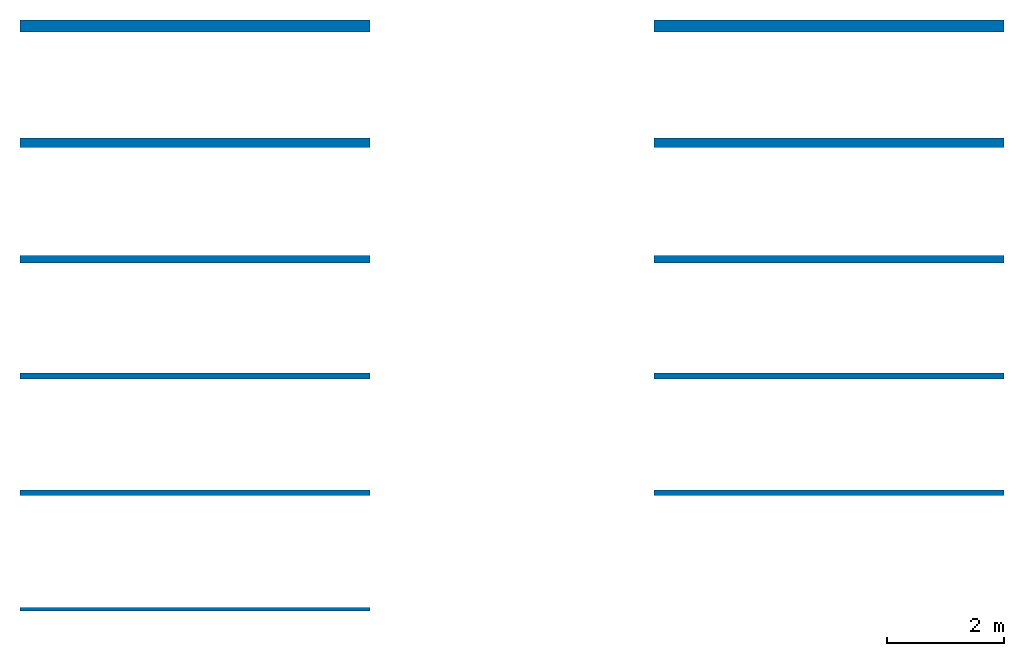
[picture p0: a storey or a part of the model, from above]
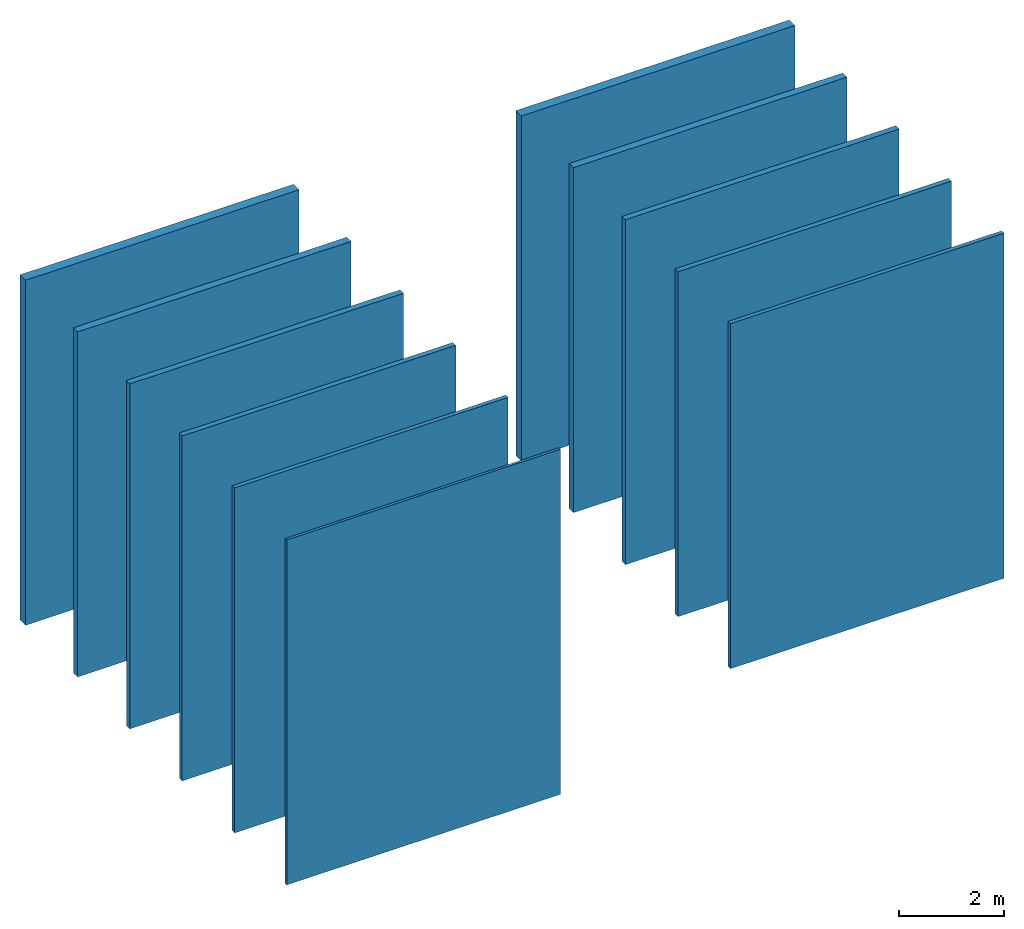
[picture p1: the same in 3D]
Properties of the parts of a building model (IFC2X3)

# File
Description: ViewDefinition [CoordinationView]
File name: Numero
Time: 2019-05-03T09:54:18
Written by: The EXPRESS Data Manager Version 5.02.0100.07 : 28 Aug 2013
Made in: 20150220_1215(x64) - Exporter 16.0.428.0 - Default UI
Comment: STEP Physical File produced by: The EXPRESS Data Manager Version 5.02.0100.07 : 28 Aug 2013 * Module: EDMstepFileFactory/EDMstandAlone * Creation date: Fri May 03 09:54:18 2019 * Host: HP-RS * Database: C:\Users\EKORU_~1\AppData\Local\Temp\{C8AE7AAE-09B5-4A10-BCEE-8D542912D24F}\ifc * Database version: 5507 * Database creation date: Fri May 03 09:54:18 2019 * Schema: IFC2X3 * Model: DataRepository.ifc * Model creation date: Fri May 03 09:54:18 2019 * Header model: DataRepository.ifc_HeaderModel * Header model creation date: Fri May 03 09:54:18 2019 * EDMuser: sdai-user * EDMgroup: sdai-group * License ID and type: 5605 : Permanent license. Expiry date: * EDMstepFileFactory options: 020000

# IfcProject, Numero
LongName: Nome; Phase: Stato

# IfcSite, Default
RefLatitude: 41, 47, 59, 999999; RefLongitude: 12, 35, 59, 999999; RefElevation: 0 mm
Altro - Categoria: Informazioni sul progetto; Data di consegna del progetto: Data; Indirizzo del progetto: Immettere l'indirizzo; Nome del cliente: Proprietario; Nome del progetto: Nome; Numero del progetto: Numero; Stato del progetto: Stato

# IfcBuilding
Pset_BuildingCommon - NumberOfStoreys: 1
Altro - Categoria: Informazioni sul progetto; Data di consegna del progetto: Data; Indirizzo del progetto: Immettere l'indirizzo; Nome del cliente: Proprietario; Nome del progetto: Nome; Numero del progetto: Numero; Stato del progetto: Stato

# IfcBuildingStorey, Livello 1
LongName: Livello 1; Elevation: 0 mm
Vincoli - Base quota altimetrica: Punto base progetto; Quota altimetrica: 0 mm
Altro - Categoria: Livelli; Famiglia: Livello: Estremità 8 mm; Famiglia e tipo: Livello: Estremità 8 mm; ID tipo: Livello: Estremità 8 mm; Tipo: Livello: Estremità 8 mm; Nome famiglia: Livello
Dati identità - Strutturale: no; Nome: Livello 1; Piano edificio: yes; Nome del tipo: Estremità 8 mm
Dimensioni - Altezza di calcolo: 0 mm
Grafica - Colore: 0; Modello di linea: Centro; Simbolo: Estremità del livello - Cerchio: Estremità del livello - Cerchio; Simbolo a estremità 1 per default: no; Simbolo a estremità 2 per default: yes; Spessore di linea: 1

# IfcWallStandardCase: Muro di base:Sistema GASBETON Evolution sp. 110 mm per tramezzatura, Muro di base:Sistema GASBETON Evolution sp. 110 mm per tramezzatura:162390
In: Livello 1
Type - PredefinedType: STANDARD; Material: GASBETON Incollarasa 5 mm, GASBETON Evolution 100 mm, GASBETON Incollarasa 5 mm
Type - Altro - Categoria: Muri; Nome famiglia: Muro di base
Type - Costruzione - Funzione: Esterno; Ripiegatura agli inserti: Non ripiegare; Ripiegatura alle estremità: Nessuno; Larghezza: 110 mm
Type - Dati identità - Descrizione: Parete rifinita formata dalla seguente stratigrafia (dall'esterno verso l'interno): rasatura armata con Incollarasa e rete da intonaco GASBETON, blocchi GASBETON Evolution, rasatura armata con Incollarasa e rete da intonaco GASBETON; Installation Guide: http://www.gasbeton.it/wp-content/uploads/2017/11/GASBETON-Guida-alla-progettazione.pdf; Modello: Soluzione tramezzatura Gasbeton Evolution; Nome del tipo: Sistema GASBETON Evolution sp. 110 mm per tramezzatura; Product data url: www.gasbeton.it; Produttore: EKORU s.r.l.; Resistenza al fuoco: EI 180; Euroclasse A1; Techinical data sheet: http://www.gasbeton.it/download/; URL: http://www.ekoru.it/; Youtube channel: https://www.youtube.com/user/bacchispa
Type - Generale - Edition number: 1; Manufacturer country: Italy; Manufacturer name: EKORU s.r.l.; Product family: walls
Type - Grafica - Colore del retino a dettaglio basso: 0
Type - Materiali e finiture - Materiale strutturale: GASBETON Evolution; Material main: Autoclaved Aerated Concrete (AAC)
Type - Proprietà analitiche - Ruvidità: 2; Assorbimento: 0.7; Coefficiente di scambio termico (U): 0.24971; Massa termica: 209837; Resistenza termica (R): 4.00464
Altro - Famiglia: Muro di base: Sistema GASBETON Evolution sp. 110 mm per tramezzatura; Famiglia e tipo: Muro di base: Sistema GASBETON Evolution sp. 110 mm per tramezzatura; ID tipo: Muro di base: Sistema GASBETON Evolution sp. 110 mm per tramezzatura; Tipo: Muro di base: Sistema GASBETON Evolution sp. 110 mm per tramezzatura
Dimensioni - Area: 48 m2; Lunghezza: 6000 mm; Volume: 5.28 m3
Fasi - Fase di creazione: Fase 1
Strutturale - Attiva modello analitico: no; Strutturale: no; Utilizzo strutturale: Non portante
Vincoli - Delimita il locale: yes; Distanza estensione base: 0 mm; Distanza estensione superiore: 0 mm; La base è associata: no; La parte superiore è associata: no; Linea di ubicazione: Linea d'asse del muro; Offset base: 0 mm; Offset superiore: 0 mm; Relativo a massa: no; Vincolo di base: Livello: Livello 1; Altezza non collegata: 8000 mm
Pset_WallCommon - LoadBearing: no; ExtendToStructure: no; IsExternal: yes; Reference: Sistema GASBETON Evolution sp. 110 mm per tramezzatura; FireRating: EI 180; Euroclasse A1; ThermalTransmittance: 0.24971 kg/K/s3
Pset_ManufacturerTypeInformation - Manufacturer: EKORU s.r.l.

# IfcWallStandardCase: Muro di base:Sistema GASBETON Evolution sp. 130 mm per tramezzatura, Muro di base:Sistema GASBETON Evolution sp. 130 mm per tramezzatura:162386
In: Livello 1
Type - PredefinedType: STANDARD; Material: GASBETON Incollarasa 5 mm, GASBETON Evolution 120 mm, GASBETON Incollarasa 5 mm
Type - Altro - Categoria: Muri; Nome famiglia: Muro di base
Type - Costruzione - Funzione: Esterno; Ripiegatura agli inserti: Non ripiegare; Ripiegatura alle estremità: Nessuno; Larghezza: 130 mm
Type - Dati identità - Descrizione: Parete rifinita formata dalla seguente stratigrafia (dall'esterno verso l'interno): rasatura armata con Incollarasa e rete da intonaco GASBETON, blocchi GASBETON Evolution, rasatura armata con Incollarasa e rete da intonaco GASBETON; Installation Guide: http://www.gasbeton.it/wp-content/uploads/2017/11/GASBETON-Guida-alla-progettazione.pdf; Modello: Soluzione tramezzatura Gasbeton Evolution; Nome del tipo: Sistema GASBETON Evolution sp. 130 mm per tramezzatura; Product data url: www.gasbeton.it; Produttore: EKORU s.r.l.; Resistenza al fuoco: EI 180; Euroclasse A1; Techinical data sheet: http://www.gasbeton.it/download/; URL: http://www.ekoru.it/; Youtube channel: https://www.youtube.com/user/bacchispa
Type - Generale - Edition number: 1; Manufacturer country: Italy; Manufacturer name: EKORU s.r.l.; Product family: walls
Type - Grafica - Colore del retino a dettaglio basso: 0
Type - Materiali e finiture - Materiale strutturale: GASBETON Evolution; Material main: Autoclaved Aerated Concrete (AAC)
Type - Proprietà analitiche - Ruvidità: 2; Assorbimento: 0.7; Coefficiente di scambio termico (U): 0.208314; Massa termica: 249308; Resistenza termica (R): 4.80044
Altro - Famiglia: Muro di base: Sistema GASBETON Evolution sp. 130 mm per tramezzatura; Famiglia e tipo: Muro di base: Sistema GASBETON Evolution sp. 130 mm per tramezzatura; ID tipo: Muro di base: Sistema GASBETON Evolution sp. 130 mm per tramezzatura; Tipo: Muro di base: Sistema GASBETON Evolution sp. 130 mm per tramezzatura
Dimensioni - Area: 48 m2; Lunghezza: 6000 mm; Volume: 6.24 m3
Fasi - Fase di creazione: Fase 1
Strutturale - Attiva modello analitico: no; Strutturale: no; Utilizzo strutturale: Non portante
Vincoli - Delimita il locale: yes; Distanza estensione base: 0 mm; Distanza estensione superiore: 0 mm; La base è associata: no; La parte superiore è associata: no; Linea di ubicazione: Linea d'asse del muro; Offset base: 0 mm; Offset superiore: 0 mm; Relativo a massa: no; Vincolo di base: Livello: Livello 1; Altezza non collegata: 8000 mm
Pset_WallCommon - LoadBearing: no; ExtendToStructure: no; IsExternal: yes; Reference: Sistema GASBETON Evolution sp. 130 mm per tramezzatura; FireRating: EI 180; Euroclasse A1; ThermalTransmittance: 0.208314 kg/K/s3
Pset_ManufacturerTypeInformation - Manufacturer: EKORU s.r.l.

# IfcWallStandardCase: Muro di base:Sistema GASBETON Evolution sp. 160 mm per tramezzatura, Muro di base:Sistema GASBETON Evolution sp. 160 mm per tramezzatura:162382
In: Livello 1
Type - PredefinedType: STANDARD; Material: GASBETON Incollarasa 5 mm, GASBETON Evolution 150 mm, GASBETON Incollarasa 5 mm
Type - Altro - Categoria: Muri; Nome famiglia: Muro di base
Type - Costruzione - Funzione: Esterno; Ripiegatura agli inserti: Non ripiegare; Ripiegatura alle estremità: Nessuno; Larghezza: 160 mm
Type - Dati identità - Descrizione: Parete rifinita formata dalla seguente stratigrafia (dall'esterno verso l'interno): rasatura armata con Incollarasa e rete da intonaco GASBETON, blocchi GASBETON Evolution, rasatura armata con Incollarasa e rete da intonaco GASBETON; Installation Guide: http://www.gasbeton.it/wp-content/uploads/2017/11/GASBETON-Guida-alla-progettazione.pdf; Modello: Soluzione tramezzatura Gasbeton Evolution; Nome del tipo: Sistema GASBETON Evolution sp. 160 mm per tramezzatura; Product data url: www.gasbeton.it; Produttore: EKORU s.r.l.; Resistenza al fuoco: EI 180; Euroclasse A1; Techinical data sheet: http://www.gasbeton.it/download/; URL: http://www.ekoru.it/; Youtube channel: https://www.youtube.com/user/bacchispa
Type - Generale - Edition number: 1; Manufacturer country: Italy; Manufacturer name: EKORU s.r.l.; Product family: walls
Type - Grafica - Colore del retino a dettaglio basso: 0
Type - Materiali e finiture - Materiale strutturale: GASBETON Evolution; Material main: Autoclaved Aerated Concrete (AAC)
Type - Proprietà analitiche - Ruvidità: 2; Assorbimento: 0.7; Coefficiente di scambio termico (U): 0.16683; Massa termica: 308515; Resistenza termica (R): 5.99414
Altro - Famiglia: Muro di base: Sistema GASBETON Evolution sp. 160 mm per tramezzatura; Famiglia e tipo: Muro di base: Sistema GASBETON Evolution sp. 160 mm per tramezzatura; ID tipo: Muro di base: Sistema GASBETON Evolution sp. 160 mm per tramezzatura; Tipo: Muro di base: Sistema GASBETON Evolution sp. 160 mm per tramezzatura
Dimensioni - Area: 48 m2; Lunghezza: 6000 mm; Volume: 7.68 m3
Fasi - Fase di creazione: Fase 1
Strutturale - Attiva modello analitico: no; Strutturale: no; Utilizzo strutturale: Non portante
Vincoli - Delimita il locale: yes; Distanza estensione base: 0 mm; Distanza estensione superiore: 0 mm; La base è associata: no; La parte superiore è associata: no; Linea di ubicazione: Linea d'asse del muro; Offset base: 0 mm; Offset superiore: 0 mm; Relativo a massa: no; Vincolo di base: Livello: Livello 1; Altezza non collegata: 8000 mm
Pset_WallCommon - LoadBearing: no; ExtendToStructure: no; IsExternal: yes; Reference: Sistema GASBETON Evolution sp. 160 mm per tramezzatura; FireRating: EI 180; Euroclasse A1; ThermalTransmittance: 0.16683 kg/K/s3
Pset_ManufacturerTypeInformation - Manufacturer: EKORU s.r.l.

# IfcWallStandardCase: Muro di base:Sistema GASBETON Evolution sp. 210 mm per tramezzatura, Muro di base:Sistema GASBETON Evolution sp. 210 mm per tramezzatura:139188
In: Livello 1
Type - PredefinedType: STANDARD; Material: GASBETON Incollarasa 5 mm, GASBETON Evolution 200 mm, GASBETON Incollarasa 5 mm
Type - Altro - Categoria: Muri; Nome famiglia: Muro di base
Type - Costruzione - Funzione: Esterno; Larghezza: 210 mm; Ripiegatura agli inserti: Non ripiegare; Ripiegatura alle estremità: Nessuno
Type - Dati identità - Descrizione: Parete rifinita formata dalla seguente stratigrafia (dall'esterno verso l'interno): rasatura armata con Incollarasa e rete da intonaco GASBETON, blocchi GASBETON Evolution, rasatura armata con Incollarasa e rete da intonaco GASBETON; Installation Guide: http://www.gasbeton.it/wp-content/uploads/2017/11/GASBETON-Guida-alla-progettazione.pdf; Modello: Soluzione tramezzatura Gasbeton Evolution; Nome del tipo: Sistema GASBETON Evolution sp. 210 mm per tramezzatura; Product data url: www.gasbeton.it; Produttore: EKORU s.r.l.; Resistenza al fuoco: EI 180; Euroclasse A1; Techinical data sheet: http://www.gasbeton.it/download/; URL: http://www.ekoru.it/; Youtube channel: https://www.youtube.com/user/bacchispa
Type - Generale - Edition number: 1; Manufacturer country: Italy; Manufacturer name: EKORU s.r.l.; Product family: walls
Type - Grafica - Colore del retino a dettaglio basso: 0
Type - Materiali e finiture - Materiale strutturale: GASBETON Evolution; Material main: Autoclaved Aerated Concrete (AAC)
Type - Proprietà analitiche - Assorbimento: 0.7; Coefficiente di scambio termico (U): 0.125256; Massa termica: 407194; Resistenza termica (R): 7.98364; Ruvidità: 2
Altro - Famiglia: Muro di base: Sistema GASBETON Evolution sp. 210 mm per tramezzatura; Famiglia e tipo: Muro di base: Sistema GASBETON Evolution sp. 210 mm per tramezzatura; ID tipo: Muro di base: Sistema GASBETON Evolution sp. 210 mm per tramezzatura; Tipo: Muro di base: Sistema GASBETON Evolution sp. 210 mm per tramezzatura
Dimensioni - Area: 48 m2; Lunghezza: 6000 mm; Volume: 10.08 m3
Fasi - Fase di creazione: Fase 1
Strutturale - Attiva modello analitico: no; Strutturale: no; Utilizzo strutturale: Non portante
Vincoli - Altezza non collegata: 8000 mm; Delimita il locale: yes; Distanza estensione base: 0 mm; Distanza estensione superiore: 0 mm; La base è associata: no; La parte superiore è associata: no; Linea di ubicazione: Linea d'asse del muro; Offset base: 0 mm; Offset superiore: 0 mm; Relativo a massa: no; Vincolo di base: Livello: Livello 1
Pset_WallCommon - Reference: Sistema GASBETON Evolution sp. 210 mm per tramezzatura; LoadBearing: no; ExtendToStructure: no; IsExternal: yes; FireRating: EI 180; Euroclasse A1; ThermalTransmittance: 0.125256 kg/K/s3
Pset_ManufacturerTypeInformation - Manufacturer: EKORU s.r.l.

# IfcWallStandardCase: Muro di base:Sistema GASBETON Evolution sp. 60 mm per tramezzatura, Muro di base:Sistema GASBETON Evolution sp. 60 mm per tramezzatura:162398
In: Livello 1
Type - PredefinedType: STANDARD; Material: GASBETON Incollarasa 5 mm, GASBETON Evolution 50 mm, GASBETON Incollarasa 5 mm
Type - Altro - Categoria: Muri; Nome famiglia: Muro di base
Type - Costruzione - Funzione: Esterno; Ripiegatura agli inserti: Non ripiegare; Ripiegatura alle estremità: Nessuno; Larghezza: 60 mm
Type - Dati identità - Descrizione: Parete rifinita formata dalla seguente stratigrafia (dall'esterno verso l'interno): rasatura armata con Incollarasa e rete da intonaco GASBETON, blocchi GASBETON Evolution, rasatura armata con Incollarasa e rete da intonaco GASBETON; Installation Guide: http://www.gasbeton.it/wp-content/uploads/2017/11/GASBETON-Guida-alla-progettazione.pdf; Modello: Soluzione tramezzatura Gasbeton Evolution; Nome del tipo: Sistema GASBETON Evolution sp. 60 mm per tramezzatura; Product data url: www.gasbeton.it; Produttore: EKORU s.r.l.; Resistenza al fuoco: Euroclasse A1; Techinical data sheet: http://www.gasbeton.it/download/; URL: http://www.ekoru.it/; Youtube channel: https://www.youtube.com/user/bacchispa
Type - Generale - Edition number: 1; Manufacturer country: Italy; Manufacturer name: EKORU s.r.l.; Product family: walls
Type - Grafica - Colore del retino a dettaglio basso: 0
Type - Materiali e finiture - Materiale strutturale: GASBETON Evolution; Material main: Autoclaved Aerated Concrete (AAC)
Type - Proprietà analitiche - Ruvidità: 2; Assorbimento: 0.7; Coefficiente di scambio termico (U): 0.496243; Massa termica: 111158; Resistenza termica (R): 2.01514
Altro - Famiglia: Muro di base: Sistema GASBETON Evolution sp. 60 mm per tramezzatura; Famiglia e tipo: Muro di base: Sistema GASBETON Evolution sp. 60 mm per tramezzatura; ID tipo: Muro di base: Sistema GASBETON Evolution sp. 60 mm per tramezzatura; Tipo: Muro di base: Sistema GASBETON Evolution sp. 60 mm per tramezzatura
Dimensioni - Area: 48 m2; Lunghezza: 6000 mm; Volume: 2.88 m3
Fasi - Fase di creazione: Fase 1
Strutturale - Attiva modello analitico: no; Strutturale: no; Utilizzo strutturale: Non portante
Vincoli - Delimita il locale: yes; Distanza estensione base: 0 mm; Distanza estensione superiore: 0 mm; La base è associata: no; La parte superiore è associata: no; Linea di ubicazione: Linea d'asse del muro; Offset base: 0 mm; Offset superiore: 0 mm; Relativo a massa: no; Vincolo di base: Livello: Livello 1; Altezza non collegata: 8000 mm
Pset_WallCommon - LoadBearing: no; ExtendToStructure: no; IsExternal: yes; Reference: Sistema GASBETON Evolution sp. 60 mm per tramezzatura; FireRating: Euroclasse A1; ThermalTransmittance: 0.496243 kg/K/s3
Pset_ManufacturerTypeInformation - Manufacturer: EKORU s.r.l.

# IfcWallStandardCase: Muro di base:Sistema GASBETON Evolution sp. 90 mm per tramezzatura, Muro di base:Sistema GASBETON Evolution sp. 90 mm per tramezzatura:162394
In: Livello 1
Type - PredefinedType: STANDARD; Material: GASBETON Incollarasa 5 mm, GASBETON Evolution 80 mm, GASBETON Incollarasa 5 mm
Type - Altro - Categoria: Muri; Nome famiglia: Muro di base
Type - Costruzione - Funzione: Esterno; Ripiegatura agli inserti: Non ripiegare; Ripiegatura alle estremità: Nessuno; Larghezza: 90 mm
Type - Dati identità - Descrizione: Parete rifinita formata dalla seguente stratigrafia (dall'esterno verso l'interno): rasatura armata con Incollarasa e rete da intonaco GASBETON, blocchi GASBETON Evolution, rasatura armata con Incollarasa e rete da intonaco GASBETON; Installation Guide: http://www.gasbeton.it/wp-content/uploads/2017/11/GASBETON-Guida-alla-progettazione.pdf; Modello: Soluzione tramezzatura Gasbeton Evolution; Nome del tipo: Sistema GASBETON Evolution sp. 90 mm per tramezzatura; Product data url: www.gasbeton.it; Produttore: EKORU s.r.l.; Resistenza al fuoco: EI 120; Euroclasse A1; Techinical data sheet: http://www.gasbeton.it/download/; URL: http://www.ekoru.it/; Youtube channel: https://www.youtube.com/user/bacchispa
Type - Generale - Edition number: 1; Manufacturer country: Italy; Manufacturer name: EKORU s.r.l.; Product family: walls
Type - Grafica - Colore del retino a dettaglio basso: 0
Type - Materiali e finiture - Materiale strutturale: GASBETON Evolution; Material main: Autoclaved Aerated Concrete (AAC)
Type - Proprietà analitiche - Ruvidità: 2; Assorbimento: 0.7; Coefficiente di scambio termico (U): 0.311639; Massa termica: 170365; Resistenza termica (R): 3.20884
Altro - Famiglia: Muro di base: Sistema GASBETON Evolution sp. 90 mm per tramezzatura; Famiglia e tipo: Muro di base: Sistema GASBETON Evolution sp. 90 mm per tramezzatura; ID tipo: Muro di base: Sistema GASBETON Evolution sp. 90 mm per tramezzatura; Tipo: Muro di base: Sistema GASBETON Evolution sp. 90 mm per tramezzatura
Dimensioni - Area: 48 m2; Lunghezza: 6000 mm; Volume: 4.32 m3
Fasi - Fase di creazione: Fase 1
Strutturale - Attiva modello analitico: no; Strutturale: no; Utilizzo strutturale: Non portante
Vincoli - Delimita il locale: yes; Distanza estensione base: 0 mm; Distanza estensione superiore: 0 mm; La base è associata: no; La parte superiore è associata: no; Linea di ubicazione: Linea d'asse del muro; Offset base: 0 mm; Offset superiore: 0 mm; Relativo a massa: no; Vincolo di base: Livello: Livello 1; Altezza non collegata: 8000 mm
Pset_WallCommon - LoadBearing: no; ExtendToStructure: no; IsExternal: yes; Reference: Sistema GASBETON Evolution sp. 90 mm per tramezzatura; FireRating: EI 120; Euroclasse A1; ThermalTransmittance: 0.311639 kg/K/s3
Pset_ManufacturerTypeInformation - Manufacturer: EKORU s.r.l.

# IfcWallStandardCase: Muro di base:Sistema GASBETON Evolution+IDRO sp. 110 mm per tramezzatura, Muro di base:Sistema GASBETON Evolution+IDRO sp. 110 mm per tramezzatura:166541
In: Livello 1
Type - PredefinedType: STANDARD; Material: GASBETON Incollarasa 5 mm, GASBETON Evolution 100 mm, GASBETON Incollarasa 5 mm
Type - Altro - Categoria: Muri; Nome famiglia: Muro di base
Type - Costruzione - Funzione: Esterno; Ripiegatura agli inserti: Non ripiegare; Ripiegatura alle estremità: Nessuno; Larghezza: 110 mm
Type - Dati identità - Descrizione: Parete rifinita formata dalla seguente stratigrafia (dall'esterno verso l'interno): rasatura armata con Incollarasa e rete da intonaco GASBETON, blocchi GASBETON Evolution, rasatura armata con Incollarasa e rete da intonaco GASBETON; Installation Guide: http://www.gasbeton.it/wp-content/uploads/2017/11/GASBETON-Guida-alla-progettazione.pdf; Modello: Soluzione tramezzatura Gasbeton Evolution con primo corso idrofobizzato; Nome del tipo: Sistema GASBETON Evolution+IDRO sp. 110 mm per tramezzatura; Product data url: www.gasbeton.it; Produttore: EKORU s.r.l.; Resistenza al fuoco: EI 180; Euroclasse A1; Techinical data sheet: http://www.gasbeton.it/download/; URL: http://www.ekoru.it/; Youtube channel: https://www.youtube.com/user/bacchispa
Type - Generale - Edition number: 1; Manufacturer country: Italy; Manufacturer name: EKORU s.r.l.; Product family: walls
Type - Grafica - Colore del retino a dettaglio basso: 0
Type - Materiali e finiture - Materiale strutturale: GASBETON Evolution; Material main: Autoclaved Aerated Concrete (AAC)
Type - Proprietà analitiche - Ruvidità: 2; Assorbimento: 0.7; Coefficiente di scambio termico (U): 0.207407; Massa termica: 291437; Resistenza termica (R): 4.82145
Altro - Famiglia: Muro di base: Sistema GASBETON Evolution+IDRO sp. 110 mm per tramezzatura; Famiglia e tipo: Muro di base: Sistema GASBETON Evolution+IDRO sp. 110 mm per tramezzatura; ID tipo: Muro di base: Sistema GASBETON Evolution+IDRO sp. 110 mm per tramezzatura; Tipo: Muro di base: Sistema GASBETON Evolution+IDRO sp. 110 mm per tramezzatura
Dimensioni - Area: 48 m2; Lunghezza: 6000 mm; Volume: 5.28 m3
Fasi - Fase di creazione: Fase 1
Strutturale - Attiva modello analitico: no; Strutturale: no; Utilizzo strutturale: Non portante
Vincoli - Delimita il locale: yes; Distanza estensione base: 0 mm; Distanza estensione superiore: 0 mm; La base è associata: no; La parte superiore è associata: no; Linea di ubicazione: Linea d'asse del muro; Offset base: 0 mm; Offset superiore: 0 mm; Relativo a massa: no; Vincolo di base: Livello: Livello 1; Altezza non collegata: 8000 mm
Pset_WallCommon - LoadBearing: no; ExtendToStructure: no; IsExternal: yes; Reference: Sistema GASBETON Evolution+IDRO sp. 110 mm per tramezzatura; FireRating: EI 180; Euroclasse A1; ThermalTransmittance: 0.207407 kg/K/s3
Pset_ManufacturerTypeInformation - Manufacturer: EKORU s.r.l.

# IfcWallStandardCase: Muro di base:Sistema GASBETON Evolution+IDRO sp. 130 mm per tramezzatura, Muro di base:Sistema GASBETON Evolution+IDRO sp. 130 mm per tramezzatura:166540
In: Livello 1
Type - PredefinedType: STANDARD; Material: GASBETON Incollarasa 5 mm, GASBETON Evolution 120 mm, GASBETON Incollarasa 5 mm
Type - Altro - Categoria: Muri; Nome famiglia: Muro di base
Type - Costruzione - Funzione: Esterno; Ripiegatura agli inserti: Non ripiegare; Ripiegatura alle estremità: Nessuno; Larghezza: 130 mm
Type - Dati identità - Descrizione: Parete rifinita formata dalla seguente stratigrafia (dall'esterno verso l'interno): rasatura armata con Incollarasa e rete da intonaco GASBETON, blocchi GASBETON Evolution, rasatura armata con Incollarasa e rete da intonaco GASBETON; Installation Guide: http://www.gasbeton.it/wp-content/uploads/2017/11/GASBETON-Guida-alla-progettazione.pdf; Modello: Soluzione tramezzatura Gasbeton Evolution con primo corso idrofobizzato; Nome del tipo: Sistema GASBETON Evolution+IDRO sp. 130 mm per tramezzatura; Product data url: www.gasbeton.it; Produttore: EKORU s.r.l.; Resistenza al fuoco: EI 180; Euroclasse A1; Techinical data sheet: http://www.gasbeton.it/download/; URL: http://www.ekoru.it/; Youtube channel: https://www.youtube.com/user/bacchispa
Type - Generale - Edition number: 1; Manufacturer country: Italy; Manufacturer name: EKORU s.r.l.; Product family: walls
Type - Grafica - Colore del retino a dettaglio basso: 0
Type - Materiali e finiture - Materiale strutturale: GASBETON Evolution; Material main: Autoclaved Aerated Concrete (AAC)
Type - Proprietà analitiche - Ruvidità: 2; Assorbimento: 0.7; Coefficiente di scambio termico (U): 0.172992; Massa termica: 347228; Resistenza termica (R): 5.78061
Altro - Famiglia: Muro di base: Sistema GASBETON Evolution+IDRO sp. 130 mm per tramezzatura; Famiglia e tipo: Muro di base: Sistema GASBETON Evolution+IDRO sp. 130 mm per tramezzatura; ID tipo: Muro di base: Sistema GASBETON Evolution+IDRO sp. 130 mm per tramezzatura; Tipo: Muro di base: Sistema GASBETON Evolution+IDRO sp. 130 mm per tramezzatura
Dimensioni - Area: 48 m2; Lunghezza: 6000 mm; Volume: 6.24 m3
Fasi - Fase di creazione: Fase 1
Strutturale - Attiva modello analitico: no; Strutturale: no; Utilizzo strutturale: Non portante
Vincoli - Delimita il locale: yes; Distanza estensione base: 0 mm; Distanza estensione superiore: 0 mm; La base è associata: no; La parte superiore è associata: no; Linea di ubicazione: Linea d'asse del muro; Offset base: 0 mm; Offset superiore: 0 mm; Relativo a massa: no; Vincolo di base: Livello: Livello 1; Altezza non collegata: 8000 mm
Pset_WallCommon - LoadBearing: no; ExtendToStructure: no; IsExternal: yes; Reference: Sistema GASBETON Evolution+IDRO sp. 130 mm per tramezzatura; FireRating: EI 180; Euroclasse A1; ThermalTransmittance: 0.172992 kg/K/s3
Pset_ManufacturerTypeInformation - Manufacturer: EKORU s.r.l.

# IfcWallStandardCase: Muro di base:Sistema GASBETON Evolution+IDRO sp. 160 mm per tramezzatura, Muro di base:Sistema GASBETON Evolution+IDRO sp. 160 mm per tramezzatura:166539
In: Livello 1
Type - PredefinedType: STANDARD; Material: GASBETON Incollarasa 5 mm, GASBETON Evolution 150 mm, GASBETON Incollarasa 5 mm
Type - Altro - Categoria: Muri; Nome famiglia: Muro di base
Type - Costruzione - Funzione: Esterno; Ripiegatura agli inserti: Non ripiegare; Ripiegatura alle estremità: Nessuno; Larghezza: 160 mm
Type - Dati identità - Descrizione: Parete rifinita formata dalla seguente stratigrafia (dall'esterno verso l'interno): rasatura armata con Incollarasa e rete da intonaco GASBETON, blocchi GASBETON Evolution, rasatura armata con Incollarasa e rete da intonaco GASBETON; Installation Guide: http://www.gasbeton.it/wp-content/uploads/2017/11/GASBETON-Guida-alla-progettazione.pdf; Modello: Soluzione tramezzatura Gasbeton Evolution con primo corso idrofobizzato; Nome del tipo: Sistema GASBETON Evolution+IDRO sp. 160 mm per tramezzatura; Product data url: www.gasbeton.it; Produttore: EKORU s.r.l.; Resistenza al fuoco: EI 180; Euroclasse A1; Techinical data sheet: http://www.gasbeton.it/download/; URL: http://www.ekoru.it/; Youtube channel: https://www.youtube.com/user/bacchispa
Type - Generale - Edition number: 1; Manufacturer country: Italy; Manufacturer name: EKORU s.r.l.; Product family: walls
Type - Grafica - Colore del retino a dettaglio basso: 0
Type - Materiali e finiture - Materiale strutturale: GASBETON Evolution; Material main: Autoclaved Aerated Concrete (AAC)
Type - Proprietà analitiche - Ruvidità: 2; Assorbimento: 0.7; Coefficiente di scambio termico (U): 0.138517; Massa termica: 430915; Resistenza termica (R): 7.21935
Altro - Famiglia: Muro di base: Sistema GASBETON Evolution+IDRO sp. 160 mm per tramezzatura; Famiglia e tipo: Muro di base: Sistema GASBETON Evolution+IDRO sp. 160 mm per tramezzatura; ID tipo: Muro di base: Sistema GASBETON Evolution+IDRO sp. 160 mm per tramezzatura; Tipo: Muro di base: Sistema GASBETON Evolution+IDRO sp. 160 mm per tramezzatura
Dimensioni - Area: 48 m2; Lunghezza: 6000 mm; Volume: 7.68 m3
Fasi - Fase di creazione: Fase 1
Strutturale - Attiva modello analitico: no; Strutturale: no; Utilizzo strutturale: Non portante
Vincoli - Delimita il locale: yes; Distanza estensione base: 0 mm; Distanza estensione superiore: 0 mm; La base è associata: no; La parte superiore è associata: no; Linea di ubicazione: Linea d'asse del muro; Offset base: 0 mm; Offset superiore: 0 mm; Relativo a massa: no; Vincolo di base: Livello: Livello 1; Altezza non collegata: 8000 mm
Pset_WallCommon - LoadBearing: no; ExtendToStructure: no; IsExternal: yes; Reference: Sistema GASBETON Evolution+IDRO sp. 160 mm per tramezzatura; FireRating: EI 180; Euroclasse A1; ThermalTransmittance: 0.138517 kg/K/s3
Pset_ManufacturerTypeInformation - Manufacturer: EKORU s.r.l.

# IfcWallStandardCase: Muro di base:Sistema GASBETON Evolution+IDRO sp. 210 mm per tramezzatura, Muro di base:Sistema GASBETON Evolution+IDRO sp. 210 mm per tramezzatura:166538
In: Livello 1
Type - PredefinedType: STANDARD; Material: GASBETON Incollarasa 5 mm, GASBETON Evolution 200 mm, GASBETON Incollarasa 5 mm
Type - Altro - Categoria: Muri; Nome famiglia: Muro di base
Type - Costruzione - Funzione: Esterno; Ripiegatura agli inserti: Non ripiegare; Ripiegatura alle estremità: Nessuno; Larghezza: 210 mm
Type - Dati identità - Descrizione: Parete rifinita formata dalla seguente stratigrafia (dall'esterno verso l'interno): rasatura armata con Incollarasa e rete da intonaco GASBETON, blocchi GASBETON Evolution, rasatura armata con Incollarasa e rete da intonaco GASBETON; Installation Guide: http://www.gasbeton.it/wp-content/uploads/2017/11/GASBETON-Guida-alla-progettazione.pdf; Modello: Soluzione tramezzatura Gasbeton Evolution con primo corso idrofobizzato; Nome del tipo: Sistema GASBETON Evolution+IDRO sp. 210 mm per tramezzatura; Product data url: www.gasbeton.it; Produttore: EKORU s.r.l.; Resistenza al fuoco: EI 180; Euroclasse A1; Techinical data sheet: http://www.gasbeton.it/download/; URL: http://www.ekoru.it/; Youtube channel: https://www.youtube.com/user/bacchispa
Type - Generale - Edition number: 1; Manufacturer country: Italy; Manufacturer name: EKORU s.r.l.; Product family: walls
Type - Grafica - Colore del retino a dettaglio basso: 0
Type - Materiali e finiture - Materiale strutturale: GASBETON Evolution; Material main: Autoclaved Aerated Concrete (AAC)
Type - Proprietà analitiche - Ruvidità: 2; Assorbimento: 0.7; Coefficiente di scambio termico (U): 0.10398; Massa termica: 570394; Resistenza termica (R): 9.61725
Altro - Famiglia: Muro di base: Sistema GASBETON Evolution+IDRO sp. 210 mm per tramezzatura; Famiglia e tipo: Muro di base: Sistema GASBETON Evolution+IDRO sp. 210 mm per tramezzatura; ID tipo: Muro di base: Sistema GASBETON Evolution+IDRO sp. 210 mm per tramezzatura; Tipo: Muro di base: Sistema GASBETON Evolution+IDRO sp. 210 mm per tramezzatura
Dimensioni - Area: 48 m2; Lunghezza: 6000 mm; Volume: 10.08 m3
Fasi - Fase di creazione: Fase 1
Strutturale - Attiva modello analitico: no; Strutturale: no; Utilizzo strutturale: Non portante
Vincoli - Delimita il locale: yes; Distanza estensione base: 0 mm; Distanza estensione superiore: 0 mm; La base è associata: no; La parte superiore è associata: no; Linea di ubicazione: Linea d'asse del muro; Offset base: 0 mm; Offset superiore: 0 mm; Relativo a massa: no; Vincolo di base: Livello: Livello 1; Altezza non collegata: 8000 mm
Pset_WallCommon - LoadBearing: no; ExtendToStructure: no; IsExternal: yes; Reference: Sistema GASBETON Evolution+IDRO sp. 210 mm per tramezzatura; FireRating: EI 180; Euroclasse A1; ThermalTransmittance: 0.10398 kg/K/s3
Pset_ManufacturerTypeInformation - Manufacturer: EKORU s.r.l.

# IfcWallStandardCase: Muro di base:Sistema GASBETON Evolution+IDRO sp. 90 mm per tramezzatura, Muro di base:Sistema GASBETON Evolution+IDRO sp. 90 mm per tramezzatura:166542
In: Livello 1
Type - PredefinedType: STANDARD; Material: GASBETON Incollarasa 5 mm, GASBETON Evolution 80 mm, GASBETON Incollarasa 5 mm
Type - Altro - Categoria: Muri; Nome famiglia: Muro di base
Type - Costruzione - Funzione: Esterno; Ripiegatura agli inserti: Non ripiegare; Ripiegatura alle estremità: Nessuno; Larghezza: 90 mm
Type - Dati identità - Descrizione: Parete rifinita formata dalla seguente stratigrafia (dall'esterno verso l'interno): rasatura armata con Incollarasa e rete da intonaco GASBETON, blocchi GASBETON Evolution, rasatura armata con Incollarasa e rete da intonaco GASBETON; Installation Guide: http://www.gasbeton.it/wp-content/uploads/2017/11/GASBETON-Guida-alla-progettazione.pdf; Modello: Soluzione tramezzatura Gasbeton Evolution con primo corso idrofobizzato; Nome del tipo: Sistema GASBETON Evolution+IDRO sp. 90 mm per tramezzatura; Product data url: www.gasbeton.it; Produttore: EKORU s.r.l.; Resistenza al fuoco: EI 120; Euroclasse A1; Techinical data sheet: http://www.gasbeton.it/download/; URL: http://www.ekoru.it/; Youtube channel: https://www.youtube.com/user/bacchispa
Type - Generale - Edition number: 1; Manufacturer country: Italy; Manufacturer name: EKORU s.r.l.; Product family: walls
Type - Grafica - Colore del retino a dettaglio basso: 0
Type - Materiali e finiture - Materiale strutturale: GASBETON Evolution; Material main: Autoclaved Aerated Concrete (AAC)
Type - Proprietà analitiche - Ruvidità: 2; Assorbimento: 0.7; Coefficiente di scambio termico (U): 0.258914; Massa termica: 235645; Resistenza termica (R): 3.86229
Altro - Famiglia: Muro di base: Sistema GASBETON Evolution+IDRO sp. 90 mm per tramezzatura; Famiglia e tipo: Muro di base: Sistema GASBETON Evolution+IDRO sp. 90 mm per tramezzatura; ID tipo: Muro di base: Sistema GASBETON Evolution+IDRO sp. 90 mm per tramezzatura; Tipo: Muro di base: Sistema GASBETON Evolution+IDRO sp. 90 mm per tramezzatura
Dimensioni - Area: 48 m2; Lunghezza: 6000 mm; Volume: 4.32 m3
Fasi - Fase di creazione: Fase 1
Strutturale - Attiva modello analitico: no; Strutturale: no; Utilizzo strutturale: Non portante
Vincoli - Delimita il locale: yes; Distanza estensione base: 0 mm; Distanza estensione superiore: 0 mm; La base è associata: no; La parte superiore è associata: no; Linea di ubicazione: Linea d'asse del muro; Offset base: 0 mm; Offset superiore: 0 mm; Relativo a massa: no; Vincolo di base: Livello: Livello 1; Altezza non collegata: 8000 mm
Pset_WallCommon - LoadBearing: no; ExtendToStructure: no; IsExternal: yes; Reference: Sistema GASBETON Evolution+IDRO sp. 90 mm per tramezzatura; FireRating: EI 120; Euroclasse A1; ThermalTransmittance: 0.258914 kg/K/s3
Pset_ManufacturerTypeInformation - Manufacturer: EKORU s.r.l.
